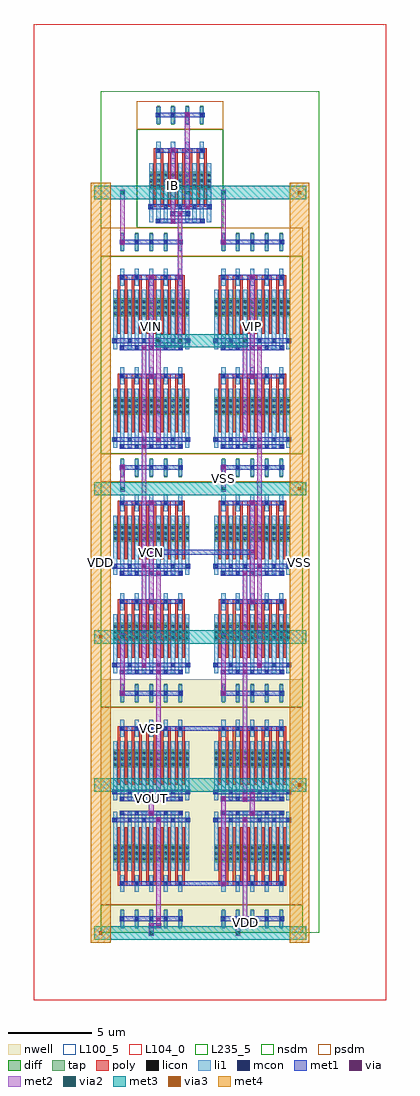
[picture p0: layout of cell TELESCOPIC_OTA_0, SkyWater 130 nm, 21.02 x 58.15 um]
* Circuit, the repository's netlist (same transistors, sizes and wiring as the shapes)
* NGSPICE file created from TELESCOPIC_OTA_0.ext - technology: sky130A

.subckt SCM_NMOS_70610444_X2_Y1_1772172714 a_200_252# a_402_462# a_147_462#
X0 a_402_462# a_200_252# a_147_462# a_147_462# sky130_fd_pr__nfet_01v8 ad=0.147 pd=1.33 as=0.147 ps=1.33 w=1.05 l=0.15 M=4
X1 a_200_252# a_200_252# a_147_462# a_147_462# sky130_fd_pr__nfet_01v8 ad=0.147 pd=1.33 as=0.147 ps=1.33 w=1.05 l=0.15 M=4
.ends

.subckt NMOS_4T_38497018_X5_Y2_1772172711 a_230_462# a_200_252# a_147_462# a_241_2408#
X0 a_230_462# a_200_252# a_147_462# a_241_2408# sky130_fd_pr__nfet_01v8 ad=0.147 pd=1.33 as=0.147 ps=1.33 w=1.05 l=0.15 M=20
.ends

.subckt PMOS_S_72546662_X5_Y1_1772172713 a_230_462# a_200_252# w_0_0#
X0 a_230_462# a_200_252# w_0_0# w_0_0# sky130_fd_pr__pfet_01v8 ad=0.147 pd=1.33 as=0.147 ps=1.33 w=1.05 l=0.15 M=10
.ends

.subckt PMOS_4T_58191883_X5_Y1_1772172712 a_230_462# a_200_252# w_0_0# a_147_462#
X0 a_230_462# a_200_252# a_147_462# w_0_0# sky130_fd_pr__pfet_01v8 ad=0.147 pd=1.33 as=0.147 ps=1.33 w=1.05 l=0.15 M=10
.ends

.subckt TELESCOPIC_OTA_0 IB VCN VOUT VIP VIN VCP VSS VDD
XSCM_NMOS_70610444_X2_Y1_1772172714_0 IB m1_914_8540# VSS SCM_NMOS_70610444_X2_Y1_1772172714
XNMOS_4T_38497018_X5_Y2_1772172711_0 m2_488_4368# VIN m1_914_8540# VSS NMOS_4T_38497018_X5_Y2_1772172711
XNMOS_4T_38497018_X5_Y2_1772172711_2 VOUT VCN m2_488_4368# VSS NMOS_4T_38497018_X5_Y2_1772172711
XNMOS_4T_38497018_X5_Y2_1772172711_1 m2_1864_4368# VIP m1_914_8540# VSS NMOS_4T_38497018_X5_Y2_1772172711
XNMOS_4T_38497018_X5_Y2_1772172711_3 m1_946_560# VCN m2_1864_4368# VSS NMOS_4T_38497018_X5_Y2_1772172711
XPMOS_S_72546662_X5_Y1_1772172713_0 m1_570_1400# m1_946_560# VDD PMOS_S_72546662_X5_Y1_1772172713
XPMOS_S_72546662_X5_Y1_1772172713_1 m1_1774_1400# m1_946_560# VDD PMOS_S_72546662_X5_Y1_1772172713
XPMOS_4T_58191883_X5_Y1_1772172712_0 VOUT VCP VDD m1_570_1400# PMOS_4T_58191883_X5_Y1_1772172712
XPMOS_4T_58191883_X5_Y1_1772172712_1 m1_946_560# VCP VDD m1_1774_1400# PMOS_4T_58191883_X5_Y1_1772172712
.ends

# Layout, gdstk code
from math import pi, radians
import gdstk
lib = gdstk.Library(unit=1e-6, precision=1e-09)
def R(c, l, rs):  # rectangles x0, y0, x1, y1
    for r in rs: c.add(gdstk.rectangle(r[:2], r[2:], *l))
def A(c, l, x, y, w, h, nx, ny, dx, dy):  # array of equal rectangles
    R(c, l, [(x+i*dx, y+j*dy, x+i*dx+w, y+j*dy+h) for i in range(nx) for j in range(ny)])
def P(c, l, *ps):  # polygons
    for p in ps: c.add(gdstk.Polygon(p, *l))
nwell = (64, 20)
diff = (65, 20)
tap = (65, 44)
poly = (66, 20)
licon = (66, 44)
li1 = (67, 20)
mcon = (67, 44)
met1 = (68, 20)
via = (68, 44)
met2 = (69, 20)
via2 = (69, 44)
met3 = (70, 20)
via3 = (70, 44)
met4 = (71, 20)
nsdm = (93, 44)
psdm = (94, 20)
L100_5 = (100, 5)
L104_0 = (104, 0)
L235_5 = (235, 5)

scm_nmos_70610444_x2_y1_ = lib.new_cell('SCM_NMOS_70610444_X2_Y1_1772172714')
R(scm_nmos_70610444_x2_y1_, diff, [(0.735,2.31,4.425,3.36)])
A(scm_nmos_70610444_x2_y1_, tap, 1.205, 6.16, 0.17, 1.12, 4, 1, 0.86, 0)
A(scm_nmos_70610444_x2_y1_, poly, 1, 1.26, 0.15, 3.36, 8, 1, 0.43, 0)
A(scm_nmos_70610444_x2_y1_, poly, 1, 4.485, 0.58, 0.27, 4, 1, 0.86, 0)
A(scm_nmos_70610444_x2_y1_, licon, 0.775, 2.39, 0.17, 0.17, 3, 3, 0.43, 0.34)
A(scm_nmos_70610444_x2_y1_, licon, 1.635, 2.39, 0.17, 0.17, 3, 3, 0.43, 0.34)
A(scm_nmos_70610444_x2_y1_, licon, 2.495, 2.39, 0.17, 0.17, 3, 3, 0.43, 0.34)
A(scm_nmos_70610444_x2_y1_, licon, 3.355, 2.39, 0.17, 0.17, 3, 3, 0.43, 0.34)
A(scm_nmos_70610444_x2_y1_, licon, 1.205, 4.535, 0.17, 0.17, 4, 2, 0.86, 2.1)
A(scm_nmos_70610444_x2_y1_, li1, 0.735, 0.335, 0.25, 3.53, 9, 1, 0.43, 0)
A(scm_nmos_70610444_x2_y1_, li1, 1.165, 4.115, 0.25, 1.01, 4, 2, 0.86, 2.1)
A(scm_nmos_70610444_x2_y1_, mcon, 0.775, 1.175, 0.17, 0.17, 5, 1, 0.86, 0)
A(scm_nmos_70610444_x2_y1_, mcon, 1.205, 4.535, 0.17, 0.17, 4, 2, 0.86, 2.1)
R(scm_nmos_70610444_x2_y1_, mcon, [(1.205,0.335,1.375,0.505), (3.785,0.335,3.955,0.505), (2.065,0.755,2.235,0.925), (2.925,0.755,3.095,0.925)])
R(scm_nmos_70610444_x2_y1_, met1, [(1.12,0.28,4.04,0.56), (1.98,0.7,3.18,0.98), (0.69,1.12,4.47,1.4), (1.12,4.48,4.04,4.76), (1.12,6.58,4.04,6.86)])
R(scm_nmos_70610444_x2_y1_, via, [(2.075,0.345,2.225,0.495), (2.935,1.185,3.085,1.335), (2.075,4.545,2.225,4.695), (2.935,6.645,3.085,6.795)])
R(scm_nmos_70610444_x2_y1_, met2, [(2.01,0.26,2.29,4.78), (2.87,1.1,3.15,6.88)])
R(scm_nmos_70610444_x2_y1_, nsdm, [(0,0,5.16,5.88)])
R(scm_nmos_70610444_x2_y1_, psdm, [(0,5.88,5.16,7.56)])
R(scm_nmos_70610444_x2_y1_, L100_5, [(0,0,5.16,7.56)])

pmos_s_72546662_x5_y1_17 = lib.new_cell('PMOS_S_72546662_X5_Y1_1772172713')
R(pmos_s_72546662_x5_y1_17, nwell, [(0,0,6.02,7.56)])
R(pmos_s_72546662_x5_y1_17, diff, [(0.735,2.31,5.285,3.36)])
A(pmos_s_72546662_x5_y1_17, tap, 1.205, 6.16, 0.17, 1.12, 5, 1, 0.86, 0)
A(pmos_s_72546662_x5_y1_17, poly, 1, 1.26, 0.15, 3.36, 10, 1, 0.43, 0)
A(pmos_s_72546662_x5_y1_17, poly, 1, 4.485, 0.58, 0.27, 5, 1, 0.86, 0)
A(pmos_s_72546662_x5_y1_17, licon, 0.775, 2.39, 0.17, 0.17, 3, 3, 0.43, 0.34)
A(pmos_s_72546662_x5_y1_17, licon, 1.635, 2.39, 0.17, 0.17, 3, 3, 0.43, 0.34)
A(pmos_s_72546662_x5_y1_17, licon, 2.495, 2.39, 0.17, 0.17, 3, 3, 0.43, 0.34)
A(pmos_s_72546662_x5_y1_17, licon, 3.355, 2.39, 0.17, 0.17, 3, 3, 0.43, 0.34)
A(pmos_s_72546662_x5_y1_17, licon, 4.215, 2.39, 0.17, 0.17, 3, 3, 0.43, 0.34)
A(pmos_s_72546662_x5_y1_17, licon, 1.205, 4.535, 0.17, 0.17, 5, 2, 0.86, 2.1)
A(pmos_s_72546662_x5_y1_17, li1, 0.735, 0.335, 0.25, 3.53, 11, 1, 0.43, 0)
A(pmos_s_72546662_x5_y1_17, li1, 1.165, 4.115, 0.25, 1.01, 5, 2, 0.86, 2.1)
A(pmos_s_72546662_x5_y1_17, mcon, 1.205, 0.335, 0.17, 0.17, 5, 2, 0.86, 4.2)
A(pmos_s_72546662_x5_y1_17, mcon, 0.775, 0.755, 0.17, 0.17, 6, 1, 0.86, 0)
A(pmos_s_72546662_x5_y1_17, mcon, 1.205, 6.635, 0.17, 0.17, 5, 1, 0.86, 0)
R(pmos_s_72546662_x5_y1_17, met1, [(1.12,0.28,4.9,0.56), (0.69,0.7,5.33,0.98), (1.12,4.48,4.9,4.76), (1.12,6.58,4.9,6.86)])
R(pmos_s_72546662_x5_y1_17, via, [(3.365,0.765,3.515,0.915), (3.365,6.645,3.515,6.795)])
R(pmos_s_72546662_x5_y1_17, met2, [(3.3,0.68,3.58,6.88)])
R(pmos_s_72546662_x5_y1_17, nsdm, [(0,5.88,6.02,7.56)])
R(pmos_s_72546662_x5_y1_17, psdm, [(0,0,6.02,5.88)])
R(pmos_s_72546662_x5_y1_17, L100_5, [(0,0,6.02,7.56)])

nmos_4t_38497018_x5_y2_1 = lib.new_cell('NMOS_4T_38497018_X5_Y2_1772172711')
R(nmos_4t_38497018_x5_y2_1, diff, [(0.735,2.31,5.285,3.36), (0.735,8.19,5.285,9.24)])
A(nmos_4t_38497018_x5_y2_1, tap, 1.205, 12.04, 0.17, 1.12, 5, 1, 0.86, 0)
A(nmos_4t_38497018_x5_y2_1, poly, 1, 1.26, 0.15, 3.36, 10, 2, 0.43, 5.88)
A(nmos_4t_38497018_x5_y2_1, poly, 1, 4.485, 0.58, 0.27, 5, 2, 0.86, 5.88)
A(nmos_4t_38497018_x5_y2_1, licon, 0.775, 2.39, 0.17, 0.17, 3, 3, 0.43, 0.34)
A(nmos_4t_38497018_x5_y2_1, licon, 1.635, 2.39, 0.17, 0.17, 3, 3, 0.43, 0.34)
A(nmos_4t_38497018_x5_y2_1, licon, 2.495, 2.39, 0.17, 0.17, 3, 3, 0.43, 0.34)
A(nmos_4t_38497018_x5_y2_1, licon, 3.355, 2.39, 0.17, 0.17, 3, 3, 0.43, 0.34)
A(nmos_4t_38497018_x5_y2_1, licon, 4.215, 2.39, 0.17, 0.17, 3, 3, 0.43, 0.34)
A(nmos_4t_38497018_x5_y2_1, licon, 1.205, 4.535, 0.17, 0.17, 5, 2, 0.86, 5.88)
A(nmos_4t_38497018_x5_y2_1, licon, 0.775, 8.27, 0.17, 0.17, 3, 3, 0.43, 0.34)
A(nmos_4t_38497018_x5_y2_1, licon, 1.635, 8.27, 0.17, 0.17, 3, 3, 0.43, 0.34)
A(nmos_4t_38497018_x5_y2_1, licon, 2.495, 8.27, 0.17, 0.17, 3, 3, 0.43, 0.34)
A(nmos_4t_38497018_x5_y2_1, licon, 3.355, 8.27, 0.17, 0.17, 3, 3, 0.43, 0.34)
A(nmos_4t_38497018_x5_y2_1, licon, 4.215, 8.27, 0.17, 0.17, 3, 3, 0.43, 0.34)
R(nmos_4t_38497018_x5_y2_1, licon, [(1.205,12.515,1.375,12.685), (1.205,12.515,1.375,12.685), (2.065,12.515,2.235,12.685), (2.065,12.515,2.235,12.685), (2.925,12.515,3.095,12.685), (2.925,12.515,3.095,12.685), (3.785,12.515,3.955,12.685), (3.785,12.515,3.955,12.685), (4.645,12.515,4.815,12.685), (4.645,12.515,4.815,12.685)])
A(nmos_4t_38497018_x5_y2_1, li1, 0.735, 0.335, 0.25, 3.53, 11, 2, 0.43, 5.88)
A(nmos_4t_38497018_x5_y2_1, li1, 1.165, 4.115, 0.25, 1.01, 5, 2, 0.86, 5.88)
A(nmos_4t_38497018_x5_y2_1, li1, 1.165, 12.095, 0.25, 1.01, 5, 1, 0.86, 0)
A(nmos_4t_38497018_x5_y2_1, mcon, 1.205, 0.335, 0.17, 0.17, 5, 2, 0.86, 4.2)
A(nmos_4t_38497018_x5_y2_1, mcon, 0.775, 0.755, 0.17, 0.17, 6, 2, 0.86, 5.88)
A(nmos_4t_38497018_x5_y2_1, mcon, 1.205, 6.215, 0.17, 0.17, 5, 2, 0.86, 4.2)
A(nmos_4t_38497018_x5_y2_1, mcon, 1.205, 12.515, 0.17, 0.17, 5, 1, 0.86, 0)
R(nmos_4t_38497018_x5_y2_1, met1, [(1.12,0.28,4.9,0.56), (0.69,0.7,5.33,0.98), (1.12,4.48,4.9,4.76), (1.12,6.16,4.9,6.44), (0.69,6.58,5.33,6.86), (1.12,10.36,4.9,10.64), (1.12,12.46,4.9,12.74)])
R(nmos_4t_38497018_x5_y2_1, via, [(2.505,0.345,2.655,0.495), (3.365,0.765,3.515,0.915), (2.935,4.545,3.085,4.695), (2.505,6.225,2.655,6.375), (3.365,6.645,3.515,6.795), (2.935,10.425,3.085,10.575)])
R(nmos_4t_38497018_x5_y2_1, met2, [(2.44,0.26,2.72,6.46), (3.3,0.68,3.58,6.88), (2.87,4.46,3.15,10.66)])
R(nmos_4t_38497018_x5_y2_1, nsdm, [(0,0,6.02,11.76)])
R(nmos_4t_38497018_x5_y2_1, psdm, [(0,11.76,6.02,13.44)])
R(nmos_4t_38497018_x5_y2_1, L100_5, [(0,0,6.02,13.44)])

pmos_4t_58191883_x5_y1_1 = lib.new_cell('PMOS_4T_58191883_X5_Y1_1772172712')
R(pmos_4t_58191883_x5_y1_1, nwell, [(0,0,6.02,7.56)])
R(pmos_4t_58191883_x5_y1_1, diff, [(0.735,2.31,5.285,3.36)])
A(pmos_4t_58191883_x5_y1_1, tap, 1.205, 6.16, 0.17, 1.12, 5, 1, 0.86, 0)
A(pmos_4t_58191883_x5_y1_1, poly, 1, 1.26, 0.15, 3.36, 10, 1, 0.43, 0)
A(pmos_4t_58191883_x5_y1_1, poly, 1, 4.485, 0.58, 0.27, 5, 1, 0.86, 0)
A(pmos_4t_58191883_x5_y1_1, licon, 0.775, 2.39, 0.17, 0.17, 3, 3, 0.43, 0.34)
A(pmos_4t_58191883_x5_y1_1, licon, 1.635, 2.39, 0.17, 0.17, 3, 3, 0.43, 0.34)
A(pmos_4t_58191883_x5_y1_1, licon, 2.495, 2.39, 0.17, 0.17, 3, 3, 0.43, 0.34)
A(pmos_4t_58191883_x5_y1_1, licon, 3.355, 2.39, 0.17, 0.17, 3, 3, 0.43, 0.34)
A(pmos_4t_58191883_x5_y1_1, licon, 4.215, 2.39, 0.17, 0.17, 3, 3, 0.43, 0.34)
A(pmos_4t_58191883_x5_y1_1, licon, 1.205, 4.535, 0.17, 0.17, 5, 2, 0.86, 2.1)
A(pmos_4t_58191883_x5_y1_1, li1, 0.735, 0.335, 0.25, 3.53, 11, 1, 0.43, 0)
A(pmos_4t_58191883_x5_y1_1, li1, 1.165, 4.115, 0.25, 1.01, 5, 2, 0.86, 2.1)
A(pmos_4t_58191883_x5_y1_1, mcon, 1.205, 0.335, 0.17, 0.17, 5, 2, 0.86, 4.2)
A(pmos_4t_58191883_x5_y1_1, mcon, 0.775, 0.755, 0.17, 0.17, 6, 1, 0.86, 0)
A(pmos_4t_58191883_x5_y1_1, mcon, 1.205, 6.635, 0.17, 0.17, 5, 1, 0.86, 0)
R(pmos_4t_58191883_x5_y1_1, met1, [(1.12,0.28,4.9,0.56), (0.69,0.7,5.33,0.98), (1.12,4.48,4.9,4.76), (1.12,6.58,4.9,6.86)])
R(pmos_4t_58191883_x5_y1_1, nsdm, [(0,5.88,6.02,7.56)])
R(pmos_4t_58191883_x5_y1_1, psdm, [(0,0,6.02,5.88)])
R(pmos_4t_58191883_x5_y1_1, L100_5, [(0,0,6.02,7.56)])

telescopic_ota_0 = lib.new_cell('TELESCOPIC_OTA_0')
R(telescopic_ota_0, met1, [(2.85,0.28,3.17,0.56), (2.85,0.28,3.17,0.56), (2.85,0.28,3.17,0.56), (2.85,0.28,3.17,0.56), (3.01,0.28,3.44,0.56), (3.28,0.28,3.6,0.56), (3.28,0.28,3.6,0.56), (3.28,0.28,3.6,0.56), (3.28,0.28,3.6,0.56), (8.01,0.28,8.33,0.56), (8.01,0.28,8.33,0.56), (8.01,0.28,8.33,0.56), (8.01,0.28,8.33,0.56), (8.01,0.28,8.33,0.56), (8.17,0.28,8.6,0.56), (8.44,0.28,8.76,0.56), (8.44,0.28,8.76,0.56), (8.44,0.28,8.76,0.56), (8.44,0.28,8.76,0.56), (8.44,0.28,8.76,0.56), (4.73,2.8,7.31,3.08), (7.15,2.8,7.47,3.08), (7.15,2.8,7.47,3.08), (7.15,2.8,7.47,3.08), (7.15,2.8,7.47,3.08), (2.85,7,3.17,7.28), (2.85,7,3.17,7.28), (8.87,7,9.19,7.28), (8.87,7,9.19,7.28), (3.28,7.84,3.6,8.12), (3.28,7.84,3.6,8.12), (7.15,7.84,7.47,8.12), (7.15,7.84,7.47,8.12), (7.15,7.84,7.47,8.12), (7.15,7.84,7.47,8.12), (8.44,7.84,8.76,8.12), (8.44,7.84,8.76,8.12), (2.85,8.26,3.17,8.54), (2.85,8.26,3.17,8.54), (8.87,8.26,9.19,8.54), (8.87,8.26,9.19,8.54), (4.73,12.04,7.31,12.32), (1.13,14.14,1.45,14.42), (1.13,14.14,1.45,14.42), (7.15,14.14,7.47,14.42), (7.15,14.14,7.47,14.42), (7.15,14.14,7.47,14.42), (2.85,22.54,3.17,22.82), (2.85,22.54,3.17,22.82), (3.01,22.54,9.03,22.82), (8.87,22.54,9.19,22.82), (8.87,22.54,9.19,22.82), (1.13,27.58,1.45,27.86), (1.13,27.58,1.45,27.86), (1.13,27.58,1.45,27.86), (1.13,27.58,1.45,27.86), (7.15,27.58,7.47,27.86), (7.15,27.58,7.47,27.86), (7.15,27.58,7.47,27.86), (7.15,27.58,7.47,27.86), (7.15,27.58,7.47,27.86), (1.13,41.02,1.45,41.3), (1.13,41.02,1.45,41.3), (7.15,41.02,7.47,41.3), (7.15,41.02,7.47,41.3), (7.15,41.02,7.47,41.3), (4.57,42.7,4.89,42.98), (4.57,42.7,4.89,42.98)])
P(telescopic_ota_0, met1, [(0,0),(0,0),(0,0),(0,0)],
  [(0,0),(0,0),(0,0),(0,0)],
  [(0,0),(0,0),(0,0),(0,0)],
  [(0,0),(0,0),(0,0),(0,0)],
  [(0,0),(0,0),(0,0),(0,0)],
  [(0,0),(0,0),(0,0),(0,0)],
  [(0,0),(0,0),(0,0),(0,0)],
  [(0,0),(0,0),(0,0),(0,0)],
  [(0,0),(0,0),(0,0),(0,0)],
  [(0,0),(0,0),(0,0),(0,0)],
  [(0,0),(0,0),(0,0),(0,0)],
  [(0,0),(0,0),(0,0),(0,0)],
  [(0,0),(0,0),(0,0),(0,0)],
  [(0,0),(0,0),(0,0),(0,0)],
  [(0,0),(0,0),(0,0),(0,0)],
  [(0,0),(0,0),(0,0),(0,0)],
  [(0,0),(0,0),(0,0),(0,0)],
  [(0,0),(0,0),(0,0),(0,0)],
  [(0,0),(0,0),(0,0),(0,0)])
R(telescopic_ota_0, via, [(2.935,0.345,3.085,0.495), (2.935,0.345,3.085,0.495), (2.935,0.345,3.085,0.495), (2.935,0.345,3.085,0.495), (3.365,0.345,3.515,0.495), (3.365,0.345,3.515,0.495), (3.365,0.345,3.515,0.495), (3.365,0.345,3.515,0.495), (8.095,0.345,8.245,0.495), (8.095,0.345,8.245,0.495), (8.095,0.345,8.245,0.495), (8.095,0.345,8.245,0.495), (8.095,0.345,8.245,0.495), (8.525,0.345,8.675,0.495), (8.525,0.345,8.675,0.495), (8.525,0.345,8.675,0.495), (8.525,0.345,8.675,0.495), (8.525,0.345,8.675,0.495), (7.235,2.865,7.385,3.015), (7.235,2.865,7.385,3.015), (7.235,2.865,7.385,3.015), (7.235,2.865,7.385,3.015), (2.935,7.065,3.085,7.215), (2.935,7.065,3.085,7.215), (8.955,7.065,9.105,7.215), (8.955,7.065,9.105,7.215), (3.365,7.905,3.515,8.055), (3.365,7.905,3.515,8.055), (7.235,7.905,7.385,8.055), (7.235,7.905,7.385,8.055), (7.235,7.905,7.385,8.055), (7.235,7.905,7.385,8.055), (8.525,7.905,8.675,8.055), (8.525,7.905,8.675,8.055), (2.935,8.325,3.085,8.475), (2.935,8.325,3.085,8.475), (8.955,8.325,9.105,8.475), (8.955,8.325,9.105,8.475), (1.215,14.205,1.365,14.355), (1.215,14.205,1.365,14.355), (7.235,14.205,7.385,14.355), (7.235,14.205,7.385,14.355), (7.235,14.205,7.385,14.355), (2.935,22.605,3.085,22.755), (2.935,22.605,3.085,22.755), (8.955,22.605,9.105,22.755), (8.955,22.605,9.105,22.755), (1.215,27.645,1.365,27.795), (1.215,27.645,1.365,27.795), (1.215,27.645,1.365,27.795), (1.215,27.645,1.365,27.795), (7.235,27.645,7.385,27.795), (7.235,27.645,7.385,27.795), (7.235,27.645,7.385,27.795), (7.235,27.645,7.385,27.795), (7.235,27.645,7.385,27.795), (1.215,41.085,1.365,41.235), (1.215,41.085,1.365,41.235), (7.235,41.085,7.385,41.235), (7.235,41.085,7.385,41.235), (7.235,41.085,7.385,41.235), (4.655,42.765,4.805,42.915), (4.655,42.765,4.805,42.915)])
R(telescopic_ota_0, met2, [(2.87,-0.185,3.15,0.185), (2.87,-0.185,3.15,0.185), (2.87,-0.185,3.15,0.185), (2.87,-0.185,3.15,0.185), (8.03,-0.185,8.31,0.185), (8.03,-0.185,8.31,0.185), (8.03,-0.185,8.31,0.185), (8.03,-0.185,8.31,0.185), (8.03,-0.185,8.31,0.185), (2.87,0,3.15,0.42), (8.03,0,8.31,0.42), (2.87,0.26,3.15,0.58), (2.87,0.26,3.15,0.58), (2.87,0.26,3.15,0.58), (2.87,0.26,3.15,0.58), (3.3,0.26,3.58,0.58), (3.3,0.26,3.58,0.58), (3.3,0.26,3.58,0.58), (3.3,0.26,3.58,0.58), (8.03,0.26,8.31,0.58), (8.03,0.26,8.31,0.58), (8.03,0.26,8.31,0.58), (8.03,0.26,8.31,0.58), (8.03,0.26,8.31,0.58), (8.46,0.26,8.74,0.58), (8.46,0.26,8.74,0.58), (8.46,0.26,8.74,0.58), (8.46,0.26,8.74,0.58), (8.46,0.26,8.74,0.58), (3.3,0.42,3.58,0.84), (8.46,0.42,8.74,0.84), (7.17,2.78,7.45,3.1), (7.17,2.78,7.45,3.1), (7.17,2.78,7.45,3.1), (7.17,2.78,7.45,3.1), (7.17,2.94,7.45,7.98), (2.87,6.98,3.15,7.3), (2.87,6.98,3.15,7.3), (8.89,6.98,9.17,7.3), (8.89,6.98,9.17,7.3), (2.87,7.14,3.15,8.4), (8.89,7.14,9.17,8.4), (3.3,7.82,3.58,8.14), (3.3,7.82,3.58,8.14), (7.17,7.82,7.45,8.14), (7.17,7.82,7.45,8.14), (7.17,7.82,7.45,8.14), (7.17,7.82,7.45,8.14), (8.46,7.82,8.74,8.14), (8.46,7.82,8.74,8.14), (3.3,7.98,3.58,15.54), (8.46,7.98,8.74,15.54), (2.87,8.24,3.15,8.56), (2.87,8.24,3.15,8.56), (8.89,8.24,9.17,8.56), (8.89,8.24,9.17,8.56), (1.15,14.12,1.43,14.44), (1.15,14.12,1.43,14.44), (7.17,14.12,7.45,14.44), (7.17,14.12,7.45,14.44), (7.17,14.12,7.45,14.44), (1.15,14.28,1.43,17.64), (7.17,14.28,7.45,17.64), (1.15,17.455,1.43,17.825), (1.15,17.455,1.43,17.825), (7.17,17.455,7.45,17.825), (7.17,17.455,7.45,17.825), (7.17,17.455,7.45,17.825), (2.44,21.84,2.72,28.98), (9.32,21.84,9.6,28.98), (2.87,22.52,3.15,22.84), (2.87,22.52,3.15,22.84), (8.89,22.52,9.17,22.84), (8.89,22.52,9.17,22.84), (1.15,26.275,1.43,26.645), (1.15,26.275,1.43,26.645), (1.15,26.275,1.43,26.645), (1.15,26.275,1.43,26.645), (7.17,26.275,7.45,26.645), (7.17,26.275,7.45,26.645), (7.17,26.275,7.45,26.645), (7.17,26.275,7.45,26.645), (7.17,26.275,7.45,26.645), (1.15,26.46,1.43,27.72), (7.17,26.46,7.45,27.72), (1.15,27.56,1.43,27.88), (1.15,27.56,1.43,27.88), (1.15,27.56,1.43,27.88), (1.15,27.56,1.43,27.88), (7.17,27.56,7.45,27.88), (7.17,27.56,7.45,27.88), (7.17,27.56,7.45,27.88), (7.17,27.56,7.45,27.88), (7.17,27.56,7.45,27.88), (3.3,35.095,3.58,35.465), (3.3,35.095,3.58,35.465), (3.3,35.095,3.58,35.465), (3.3,35.095,3.58,35.465), (4.59,35.095,4.87,35.465), (4.59,35.095,4.87,35.465), (8.46,35.095,8.74,35.465), (8.46,35.095,8.74,35.465), (8.46,35.095,8.74,35.465), (8.46,35.095,8.74,35.465), (4.59,35.28,4.87,42.84), (1.15,41,1.43,41.32), (1.15,41,1.43,41.32), (7.17,41,7.45,41.32), (7.17,41,7.45,41.32), (7.17,41,7.45,41.32), (1.15,41.16,1.43,44.1), (7.17,41.16,7.45,44.1), (4.59,42.68,4.87,43), (4.59,42.68,4.87,43), (1.15,43.915,1.43,44.285), (1.15,43.915,1.43,44.285), (5.02,43.915,5.3,44.285), (5.02,43.915,5.3,44.285), (5.02,43.915,5.3,44.285), (5.02,43.915,5.3,44.285), (5.02,43.915,5.3,44.285), (5.02,43.915,5.3,44.285), (7.17,43.915,7.45,44.285), (7.17,43.915,7.45,44.285), (7.17,43.915,7.45,44.285)])
P(telescopic_ota_0, met2, [(0,0),(0,0),(0,0),(0,0)],
  [(0,0),(0,0),(0,0),(0,0)],
  [(0,0),(0,0),(0,0),(0,0)],
  [(0,0),(0,0),(0,0),(0,0)],
  [(0,0),(0,0),(0,0),(0,0)],
  [(0,0),(0,0),(0,0),(0,0)],
  [(0,0),(0,0),(0,0),(0,0)],
  [(0,0),(0,0),(0,0),(0,0)],
  [(0,0),(0,0),(0,0),(0,0)],
  [(0,0),(0,0),(0,0),(0,0)],
  [(0,0),(0,0),(0,0),(0,0)],
  [(0,0),(0,0),(0,0),(0,0)],
  [(0,0),(0,0),(0,0),(0,0)],
  [(0,0),(0,0),(0,0),(0,0)],
  [(0,0),(0,0),(0,0),(0,0)],
  [(0,0),(0,0),(0,0),(0,0)],
  [(0,0),(0,0),(0,0),(0,0)],
  [(0,0),(0,0),(0,0),(0,0)],
  [(0,0),(0,0),(0,0),(0,0)],
  [(0,0),(0,0),(0,0),(0,0)])
R(telescopic_ota_0, via2, [(2.91,-0.1,3.11,0.1), (2.91,-0.1,3.11,0.1), (2.91,-0.1,3.11,0.1), (2.91,-0.1,3.11,0.1), (8.07,-0.1,8.27,0.1), (8.07,-0.1,8.27,0.1), (8.07,-0.1,8.27,0.1), (8.07,-0.1,8.27,0.1), (8.07,-0.1,8.27,0.1), (1.19,17.54,1.39,17.74), (1.19,17.54,1.39,17.74), (7.21,17.54,7.41,17.74), (7.21,17.54,7.41,17.74), (7.21,17.54,7.41,17.74), (1.19,26.36,1.39,26.56), (1.19,26.36,1.39,26.56), (1.19,26.36,1.39,26.56), (1.19,26.36,1.39,26.56), (7.21,26.36,7.41,26.56), (7.21,26.36,7.41,26.56), (7.21,26.36,7.41,26.56), (7.21,26.36,7.41,26.56), (7.21,26.36,7.41,26.56), (3.34,35.18,3.54,35.38), (3.34,35.18,3.54,35.38), (3.34,35.18,3.54,35.38), (3.34,35.18,3.54,35.38), (4.63,35.18,4.83,35.38), (4.63,35.18,4.83,35.38), (8.5,35.18,8.7,35.38), (8.5,35.18,8.7,35.38), (8.5,35.18,8.7,35.38), (8.5,35.18,8.7,35.38), (1.19,44,1.39,44.2), (1.19,44,1.39,44.2), (5.06,44,5.26,44.2), (5.06,44,5.26,44.2), (5.06,44,5.26,44.2), (5.06,44,5.26,44.2), (5.06,44,5.26,44.2), (5.06,44,5.26,44.2), (7.21,44,7.41,44.2), (7.21,44,7.41,44.2), (7.21,44,7.41,44.2)])
A(telescopic_ota_0, met3, -0.4, -0.4, 4.24, 0.8, 3, 4, 3.44, 8.82)
A(telescopic_ota_0, met3, 9.92, -0.4, 2.32, 0.8, 1, 4, 0, 8.82)
A(telescopic_ota_0, met3, 11.675, 8.42, 0.33, 0.8, 1, 3, 0, 17.64)
A(telescopic_ota_0, met3, -0.4, 43.7, 4.24, 0.8, 3, 1, 3.44, 0)
R(telescopic_ota_0, met3, [(-0.165,-0.4,0.165,0.4), (2.845,-0.4,3.175,0.4), (2.845,-0.4,3.175,0.4), (2.845,-0.4,3.175,0.4), (2.845,-0.4,3.175,0.4), (8.005,-0.4,8.335,0.4), (8.005,-0.4,8.335,0.4), (8.005,-0.4,8.335,0.4), (8.005,-0.4,8.335,0.4), (8.005,-0.4,8.335,0.4), (-0.165,17.24,0.165,18.04), (1.125,17.24,1.455,18.04), (1.125,17.24,1.455,18.04), (7.145,17.24,7.475,18.04), (7.145,17.24,7.475,18.04), (7.145,17.24,7.475,18.04), (1.125,26.06,1.455,26.86), (1.125,26.06,1.455,26.86), (1.125,26.06,1.455,26.86), (1.125,26.06,1.455,26.86), (7.145,26.06,7.475,26.86), (7.145,26.06,7.475,26.86), (7.145,26.06,7.475,26.86), (7.145,26.06,7.475,26.86), (7.145,26.06,7.475,26.86), (3.275,34.88,3.605,35.68), (3.275,34.88,3.605,35.68), (3.275,34.88,3.605,35.68), (3.275,34.88,3.605,35.68), (3.44,34.88,8.6,35.68), (4.565,34.88,4.895,35.68), (4.565,34.88,4.895,35.68), (8.435,34.88,8.765,35.68), (8.435,34.88,8.765,35.68), (8.435,34.88,8.765,35.68), (8.435,34.88,8.765,35.68), (1.125,43.7,1.455,44.5), (1.125,43.7,1.455,44.5), (4.995,43.7,5.325,44.5), (4.995,43.7,5.325,44.5), (4.995,43.7,5.325,44.5), (4.995,43.7,5.325,44.5), (4.995,43.7,5.325,44.5), (4.995,43.7,5.325,44.5), (7.145,43.7,7.475,44.5), (7.145,43.7,7.475,44.5), (7.145,43.7,7.475,44.5), (9.92,43.7,12.24,44.5)])
A(telescopic_ota_0, via3, 11.74, 8.72, 0.2, 0.2, 1, 3, 0, 17.64)
R(telescopic_ota_0, via3, [(-0.1,-0.1,0.1,0.1), (-0.1,17.54,0.1,17.74)])
A(telescopic_ota_0, met4, -0.59, -0.59, 1.18, 10, 1, 4, 0, 8.82)
A(telescopic_ota_0, met4, 11.25, -0.59, 1.18, 10, 1, 4, 0, 8.82)
A(telescopic_ota_0, met4, 11.25, 8.655, 1.18, 0.33, 1, 3, 0, 17.64)
R(telescopic_ota_0, met4, [(-0.59,-0.165,0.59,0.165), (-0.59,17.475,0.59,17.805), (-0.59,34.69,0.59,39.79), (11.25,34.69,12.43,39.79), (-0.59,38.61,0.59,44.69), (11.25,38.61,12.43,44.69)])
R(telescopic_ota_0, L104_0, [(-4,-4,17.02,54.15)])
R(telescopic_ota_0, L235_5, [(0,0,13.02,50.15)])
telescopic_ota_0.add(gdstk.Reference(scm_nmos_70610444_x2_y1_, (2.15,42)))
telescopic_ota_0.add(gdstk.Reference(pmos_s_72546662_x5_y1_17, (12.04,7.56), rotation=pi))
telescopic_ota_0.add(gdstk.Reference(pmos_s_72546662_x5_y1_17, (0,7.56), x_reflection=True))
telescopic_ota_0.add(gdstk.Reference(nmos_4t_38497018_x5_y2_1, (6.02,15.12)))
telescopic_ota_0.add(gdstk.Reference(nmos_4t_38497018_x5_y2_1, (6.02,15.12), rotation=pi, x_reflection=True))
telescopic_ota_0.add(gdstk.Reference(nmos_4t_38497018_x5_y2_1, (12.04,28.56), rotation=pi, x_reflection=True))
telescopic_ota_0.add(gdstk.Reference(nmos_4t_38497018_x5_y2_1, (0,28.56)))
telescopic_ota_0.add(gdstk.Reference(pmos_4t_58191883_x5_y1_1, (6.02,7.56)))
telescopic_ota_0.add(gdstk.Reference(pmos_4t_58191883_x5_y1_1, (6.02,7.56), rotation=pi, x_reflection=True))
telescopic_ota_0.add(gdstk.Label('IB', (4.3,44.52), layer=69, texttype=5))
telescopic_ota_0.add(gdstk.Label('VCN', (3.01,22.68), layer=69, texttype=5))
telescopic_ota_0.add(gdstk.Label('VOUT', (3.01,7.98), layer=68, texttype=5))
telescopic_ota_0.add(gdstk.Label('VIP', (9.03,36.12), layer=69, texttype=5))
telescopic_ota_0.add(gdstk.Label('VIN', (3.01,36.12), layer=69, texttype=5))
telescopic_ota_0.add(gdstk.Label('VCP', (3.01,12.18), layer=68, texttype=5))
telescopic_ota_0.add(gdstk.Label('VSS', (11.84,22.05), layer=71, texttype=5))
telescopic_ota_0.add(gdstk.Label('VSS', (11.84,22.05), layer=71, texttype=5))
telescopic_ota_0.add(gdstk.Label('VSS', (11.84,22.05), layer=71, texttype=5))
telescopic_ota_0.add(gdstk.Label('VSS', (7.31,27.09), layer=69, texttype=5))
telescopic_ota_0.add(gdstk.Label('VSS', (11.84,22.05), layer=71, texttype=5))
telescopic_ota_0.add(gdstk.Label('VSS', (11.84,22.05), layer=71, texttype=5))
telescopic_ota_0.add(gdstk.Label('VSS', (11.84,22.05), layer=71, texttype=5))
telescopic_ota_0.add(gdstk.Label('VSS', (11.84,22.05), layer=71, texttype=5))
telescopic_ota_0.add(gdstk.Label('VSS', (11.84,22.05), layer=71, texttype=5))
telescopic_ota_0.add(gdstk.Label('VSS', (11.84,22.05), layer=71, texttype=5))
telescopic_ota_0.add(gdstk.Label('VSS', (11.84,22.05), layer=71, texttype=5))
telescopic_ota_0.add(gdstk.Label('VSS', (11.84,22.05), layer=71, texttype=5))
telescopic_ota_0.add(gdstk.Label('VSS', (11.84,22.05), layer=71, texttype=5))
telescopic_ota_0.add(gdstk.Label('VSS', (11.84,22.05), layer=71, texttype=5))
telescopic_ota_0.add(gdstk.Label('VSS', (11.84,22.05), layer=71, texttype=5))
telescopic_ota_0.add(gdstk.Label('VDD', (8.6,0.63), layer=69, texttype=5))
telescopic_ota_0.add(gdstk.Label('VDD', (0,22.05), layer=71, texttype=5))
telescopic_ota_0.add(gdstk.Label('VDD', (0,22.05), layer=71, texttype=5))
telescopic_ota_0.add(gdstk.Label('VDD', (0,22.05), layer=71, texttype=5))
telescopic_ota_0.add(gdstk.Label('VDD', (0,22.05), layer=71, texttype=5))
telescopic_ota_0.add(gdstk.Label('VDD', (0,22.05), layer=71, texttype=5))
telescopic_ota_0.add(gdstk.Label('VDD', (0,22.05), layer=71, texttype=5))
telescopic_ota_0.add(gdstk.Label('VDD', (0,22.05), layer=71, texttype=5))
telescopic_ota_0.add(gdstk.Label('VDD', (0,22.05), layer=71, texttype=5))
telescopic_ota_0.add(gdstk.Label('VDD', (0,22.05), layer=71, texttype=5))
telescopic_ota_0.add(gdstk.Label('VDD', (0,22.05), layer=71, texttype=5))
telescopic_ota_0.add(gdstk.Label('VDD', (0,22.05), layer=71, texttype=5))
telescopic_ota_0.add(gdstk.Label('VDD', (0,22.05), layer=71, texttype=5))
telescopic_ota_0.add(gdstk.Label('VDD', (0,22.05), layer=71, texttype=5))
telescopic_ota_0.add(gdstk.Label('VDD', (0,22.05), layer=71, texttype=5))

lib.write_gds('TELESCOPIC_OTA_0.gds')
